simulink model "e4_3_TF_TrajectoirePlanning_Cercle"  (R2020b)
settings: Solver=FixedStepAuto  StartTime=0.0  StopTime=100  FixedStep=sampleTime  RelTol=1e-3  EnableMultiTasking=on
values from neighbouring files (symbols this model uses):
  k2_d_x = 1/1    (= 1)    [e4_3_TF_TrajectoirePlanning_code.m]    (also in e4_1_Model_TrajectoirePlanning_HITL_code.m = 0.5; e4_3_Model_TrajectoirePlanning_code.m = 0.5; e4_1_TF_TrajectoirePlanning_code.m; e4_1_Model_TrajectoirePlanning_code.m = 0.5)
  k2_d_y = 1/1    (= 1)    [e4_3_TF_TrajectoirePlanning_code.m]    (also in e4_1_Model_TrajectoirePlanning_HITL_code.m = 0.377358490566; e4_3_Model_TrajectoirePlanning_code.m = 0.377358490566; e4_1_TF_TrajectoirePlanning_code.m; e4_1_Model_TrajectoirePlanning_code.m = 0.377358490566)
  k2_d_z = 10    [e4_3_TF_TrajectoirePlanning_code.m]    (also in e4_1_Model_TrajectoirePlanning_HITL_code.m; e4_3_Model_TrajectoirePlanning_code.m; e4_1_TF_TrajectoirePlanning_code.m; e4_1_Model_TrajectoirePlanning_code.m)
  k2_p_x = 1/0.8    (= 1.25)    [e4_3_TF_TrajectoirePlanning_code.m]    (also in e4_1_Model_TrajectoirePlanning_HITL_code.m = 0.645161290323; e4_3_Model_TrajectoirePlanning_code.m = 0.645161290323; e4_1_TF_TrajectoirePlanning_code.m; e4_1_Model_TrajectoirePlanning_code.m = 0.645161290323)
  k2_p_y = 1/0.8    (= 1.25)    [e4_3_TF_TrajectoirePlanning_code.m]    (also in e4_1_Model_TrajectoirePlanning_HITL_code.m = 0.4; e4_3_Model_TrajectoirePlanning_code.m = 0.4; e4_1_TF_TrajectoirePlanning_code.m; e4_1_Model_TrajectoirePlanning_code.m = 0.4)
  k2_p_yaw = 1.6    [e4_3_TF_TrajectoirePlanning_code.m]    (also in e4_1_Model_TrajectoirePlanning_HITL_code.m; e4_3_Model_TrajectoirePlanning_code.m; e4_1_TF_TrajectoirePlanning_code.m; e4_1_Model_TrajectoirePlanning_code.m)
  k2_p_z = 1    [e4_3_TF_TrajectoirePlanning_code.m]    (also in e4_1_Model_TrajectoirePlanning_HITL_code.m; e4_3_Model_TrajectoirePlanning_code.m; e4_1_TF_TrajectoirePlanning_code.m; e4_1_Model_TrajectoirePlanning_code.m)
  sampleTime = 0.01    [startSimulation.m]    (also in start.m)
  saturation_psi = 2    [startSimulation.m]    (also in start.m)
  saturation_x = 2    [startSimulation.m]    (also in start.m)
  saturation_y = 2    [startSimulation.m]    (also in start.m)
  saturation_z = 2    [startSimulation.m]    (also in start.m)
libraries: simulink x2, aerolibanimutils x1

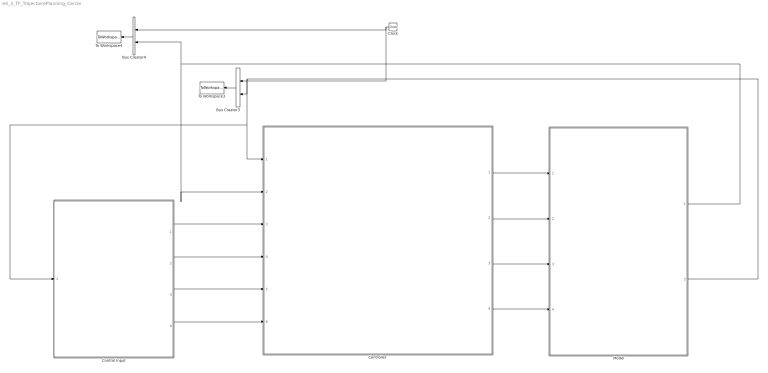
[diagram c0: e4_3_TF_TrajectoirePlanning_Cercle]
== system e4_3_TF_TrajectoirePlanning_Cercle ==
  Bus Creator3 : BusCreator  Inputs=2
  Bus Creator4 : BusCreator  Inputs=2
  Clock : Clock
  Control Input : Subsystem
  "Controller " : Subsystem
  Model : Subsystem
  To Workspace3 : ToWorkspace  VariableName=r1_pos_array  SampleTime=-1
  To Workspace4 : ToWorkspace  VariableName=r1_vel_array  SampleTime=-1
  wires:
  Clock/1 -> Bus Creator4/1, Bus Creator3/1
  Bus Creator3/1 -> To Workspace3/1
  Bus Creator4/1 -> To Workspace4/1
  Control Input/1(ux) -> "Controller "/3(Control input X)
  Control Input/2(uy) -> "Controller "/4(Control input Y)
  Control Input/3(uz) -> "Controller "/5(Control input H)
  Control Input/4(upsi) -> "Controller "/6(Control input Psi)
  Model/2(Output Position) -> "Controller "/1(Feedback Position), Control Input/1(Position Feedback), Bus Creator3/2
  Model/1(Output Velocity) -> "Controller "/2(Feedback Velocity), Bus Creator4/2
  "Controller "/1(Controller Output X) -> Model/1(Commande Input X)
  "Controller "/4(Controller Output Psi) -> Model/4(Commande Input Psi)
  "Controller "/2(Controller Output Y) -> Model/2(Commande Input Y)
  "Controller "/3(Controller Output H) -> Model/3(Commande Input H)

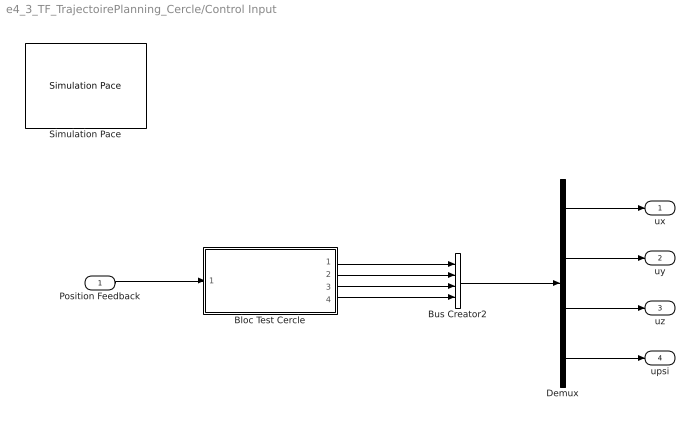
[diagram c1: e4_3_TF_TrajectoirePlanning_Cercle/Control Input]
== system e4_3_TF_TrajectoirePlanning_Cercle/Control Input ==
  Position Feedback : Inport
  Bloc Test Cercle : Subsystem
  Bus Creator2 : BusCreator  Inputs=4
  Demux : Demux
  Simulation Pace : aerolibanimutils/Simulation Pace  SimulationPace=100  SleepMode=MATLAB Thread  OutputPaceError=off  SampleTime=-1
  ux : Outport  VectorParamsAs1DForOutWhenUnconnected=off
  uy : Outport  Port=2  VectorParamsAs1DForOutWhenUnconnected=off
  uz : Outport  Port=3  VectorParamsAs1DForOutWhenUnconnected=off
  upsi : Outport  Port=4  VectorParamsAs1DForOutWhenUnconnected=off
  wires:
  Demux/2 -> uy/1
  Demux/1 -> ux/1
  Demux/3 -> uz/1
  Demux/4 -> upsi/1
  Bloc Test Cercle/2(uy) -> Bus Creator2/2
  Bloc Test Cercle/4(upsi) -> Bus Creator2/4
  Position Feedback/1 -> Bloc Test Cercle/1(Position Feedback)
  Bloc Test Cercle/3(uz) -> Bus Creator2/3
  Bus Creator2/1 -> Demux/1
  Bloc Test Cercle/1(ux) -> Bus Creator2/1

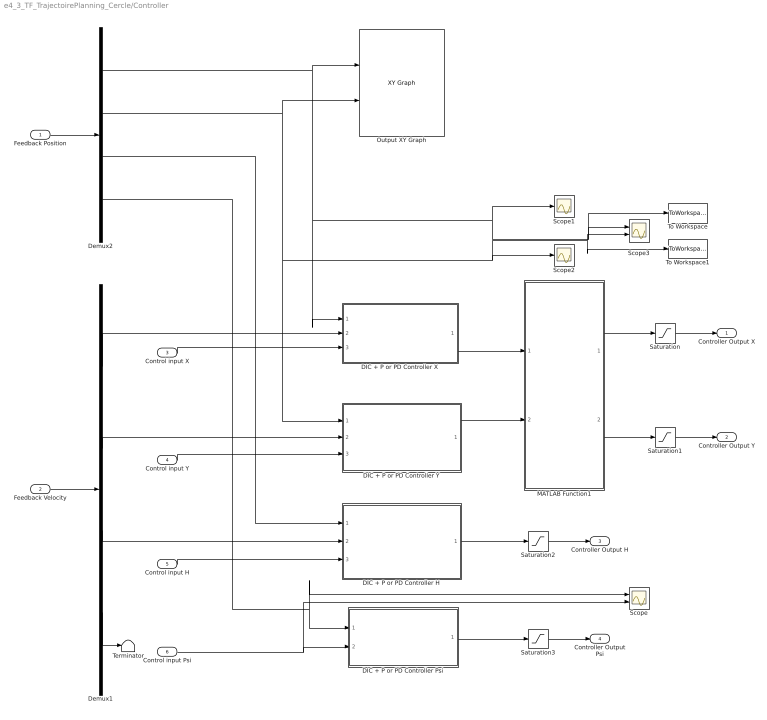
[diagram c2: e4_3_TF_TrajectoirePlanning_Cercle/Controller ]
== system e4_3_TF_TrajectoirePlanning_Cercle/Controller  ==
  Feedback Position : Inport
  Feedback Velocity : Inport  Port=2
  Control input X : Inport  Port=3
  Control input Y : Inport  Port=4
  Control input H : Inport  Port=5
  Control input Psi : Inport  Port=6
  DIC + P or PD Controller H : Subsystem
  DIC + P or PD Controller Psi : Subsystem
  DIC + P or PD Controller X : Subsystem
  DIC + P or PD Controller Y : Subsystem
  Demux1 : Demux
  Demux2 : Demux
  MATLAB Function1 : MATLAB Function  TreatAsAtomicUnit=on
  Output XY Graph : simulink/Sinks/XY Graph  xmin=-3  xmax=3  ymin=-3  ymax=3  st=-1
  Saturation : Saturate  UpperLimit=saturation_x  LowerLimit=-saturation_x
  Saturation1 : Saturate  UpperLimit=saturation_y  LowerLimit=-saturation_y
  Saturation2 : Saturate  UpperLimit=saturation_z  LowerLimit=-saturation_z
  Saturation3 : Saturate  UpperLimit=saturation_psi  LowerLimit=-saturation_psi
  Scope : Scope  NumInputPorts=2
  Scope1 : Scope
  Scope2 : Scope
  Scope3 : Scope  NumInputPorts=2
  Terminator : Terminator
  To Workspace : ToWorkspace  VariableName=x_desire  SampleTime=-1
  To Workspace1 : ToWorkspace  VariableName=y_desire  SampleTime=-1
  Controller Output X : Outport  VectorParamsAs1DForOutWhenUnconnected=off
  Controller Output Y : Outport  Port=2  VectorParamsAs1DForOutWhenUnconnected=off
  Controller Output H : Outport  Port=3  VectorParamsAs1DForOutWhenUnconnected=off
  Controller Output Psi : Outport  Port=4  VectorParamsAs1DForOutWhenUnconnected=off
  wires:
  Feedback Position/1 -> Demux2/1
  Feedback Velocity/1 -> Demux1/1
  Demux1/2 -> DIC + P or PD Controller Y/2(Feedback Velocity Y)
  Demux2/3 -> DIC + P or PD Controller H/1(Feedback Position H)
  Demux1/1 -> DIC + P or PD Controller X/2(Feedback Velocity X)
  Demux1/3 -> DIC + P or PD Controller H/2(Feedback Velocity H)
  Control input X/1 -> DIC + P or PD Controller X/3(Control Input X)
  Control input Psi/1 -> Scope/2, DIC + P or PD Controller Psi/2(Control input Psi)
  Control input H/1 -> DIC + P or PD Controller H/3(Control Input H)
  Saturation/1 -> Controller Output X/1
  Saturation1/1 -> Controller Output Y/1
  Saturation2/1 -> Controller Output H/1
  Saturation3/1 -> Controller Output Psi/1
  Control input Y/1 -> DIC + P or PD Controller Y/3(Control Input Y)
  DIC + P or PD Controller H/1(Controller Output H) -> Saturation2/1
  DIC + P or PD Controller Psi/1(Controller Output Psi) -> Saturation3/1
  Demux2/4 -> Scope/1, DIC + P or PD Controller Psi/1(Feedback Position Psi)
  Demux1/4 -> Terminator/1
  DIC + P or PD Controller Y/1(Controller Output Y) -> MATLAB Function1/2(eay)
  MATLAB Function1/2(phi) -> Saturation1/1
  MATLAB Function1/1(theta) -> Saturation/1
  DIC + P or PD Controller X/1(Controller Output X) -> MATLAB Function1/1(eax)
  Demux2/1 -> DIC + P or PD Controller X/1(Feedback Position X), Scope3/1, To Workspace/1, Scope1/1, Output XY Graph/1
  Demux2/2 -> DIC + P or PD Controller Y/1(Feedback Position Y), Scope3/2, To Workspace1/1, Scope2/1, Output XY Graph/2

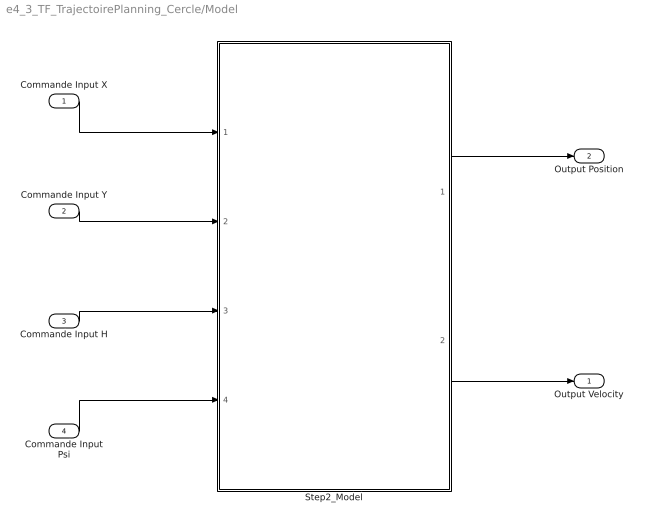
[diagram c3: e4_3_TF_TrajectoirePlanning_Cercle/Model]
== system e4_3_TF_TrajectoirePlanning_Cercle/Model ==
  Commande Input X : Inport
  Commande Input Y : Inport  Port=2
  Commande Input H : Inport  Port=3
  Commande Input Psi : Inport  Port=4
  Step2_Model : Subsystem
  Output Velocity : Outport  VectorParamsAs1DForOutWhenUnconnected=off
  Output Position : Outport  Port=2  VectorParamsAs1DForOutWhenUnconnected=off
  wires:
  Commande Input Y/1 -> Step2_Model/2(In2)
  Commande Input Psi/1 -> Step2_Model/4(In4)
  Commande Input H/1 -> Step2_Model/3(In3)
  Step2_Model/1(Position) -> Output Position/1
  Commande Input X/1 -> Step2_Model/1(In1)
  Step2_Model/2(Velocity) -> Output Velocity/1

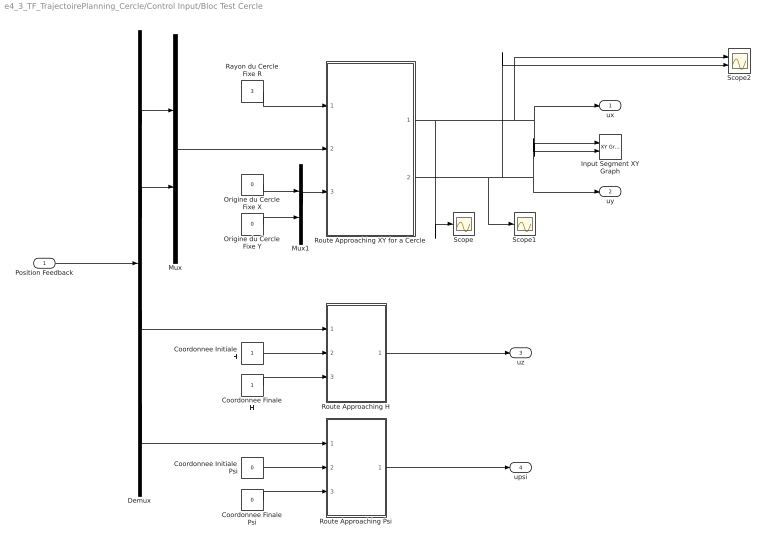
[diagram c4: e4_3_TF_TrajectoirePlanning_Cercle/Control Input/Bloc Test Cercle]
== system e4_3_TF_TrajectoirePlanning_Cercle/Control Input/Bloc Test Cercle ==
  Position Feedback : Inport
  Coordonnee Finale H : Constant
  Coordonnee Finale Psi : Constant  Value=0
  Coordonnee Initiale H : Constant
  Coordonnee Initiale Psi : Constant  Value=0
  Demux : Demux
  Input Segment XY Graph : simulink/Sinks/XY Graph  xmin=-10  xmax=10  ymin=-10  ymax=10  st=-1
  Mux : Mux  Inputs=2
  Mux1 : Mux  Inputs=2
  Origine du Cercle Fixe X : Constant  Value=0
  Origine du Cercle Fixe Y : Constant  Value=0
  Rayon du Cercle Fixe R : Constant  Value=3
  Route Approaching H : MATLAB Function  TreatAsAtomicUnit=on  SystemSampleTime=sampleTime
  Route Approaching Psi : MATLAB Function  TreatAsAtomicUnit=on  SystemSampleTime=sampleTime
  Route Approaching XY for a Cercle : MATLAB Function  TreatAsAtomicUnit=on  SystemSampleTime=sampleTime
  Scope : Scope
  Scope1 : Scope
  Scope2 : Scope  NumInputPorts=2
  ux : Outport  VectorParamsAs1DForOutWhenUnconnected=off
  uy : Outport  Port=2  VectorParamsAs1DForOutWhenUnconnected=off
  uz : Outport  Port=3  VectorParamsAs1DForOutWhenUnconnected=off
  upsi : Outport  Port=4  VectorParamsAs1DForOutWhenUnconnected=off
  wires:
  Position Feedback/1 -> Demux/1
  Coordonnee Finale H/1 -> Route Approaching H/3(P_final)
  Coordonnee Finale Psi/1 -> Route Approaching Psi/3(P_final)
  Coordonnee Initiale Psi/1 -> Route Approaching Psi/2(P_init)
  Route Approaching H/1(P_d) -> uz/1
  Route Approaching Psi/1(P_d) -> upsi/1
  Demux/3 -> Route Approaching H/1(P_feedback)
  Demux/2 -> Mux/2
  Demux/4 -> Route Approaching Psi/1(P_feedback)
  Coordonnee Initiale H/1 -> Route Approaching H/2(P_init)
  Demux/1 -> Mux/1
  Mux/1 -> Route Approaching XY for a Cercle/2(P_feedback)
  Rayon du Cercle Fixe R/1 -> Route Approaching XY for a Cercle/1(P_Rayon)
  Mux1/1 -> Route Approaching XY for a Cercle/3(P_Origine)
  Origine du Cercle Fixe X/1 -> Mux1/1
  Origine du Cercle Fixe Y/1 -> Mux1/2
  Route Approaching XY for a Cercle/2(P_dy) -> Scope2/2, uy/1, Input Segment XY Graph/2, Scope1/1
  Route Approaching XY for a Cercle/1(P_dx) -> Scope2/1, ux/1, Input Segment XY Graph/1, Scope/1

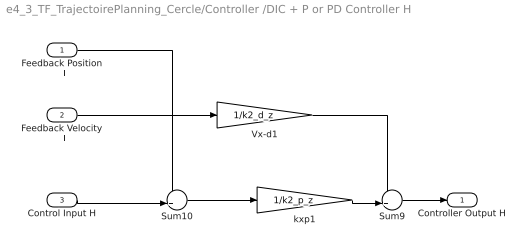
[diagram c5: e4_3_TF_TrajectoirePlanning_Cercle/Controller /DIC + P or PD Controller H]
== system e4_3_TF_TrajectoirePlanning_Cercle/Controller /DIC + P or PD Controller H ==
  Feedback Position H : Inport
  Feedback Velocity H : Inport  Port=2
  Control Input H : Inport  Port=3
  Sum10 : Sum  Inputs=-+|
  Sum9 : Sum  Inputs=-+|
  Vx-d1 : Gain  Gain=1/k2_d_z
  kxp1 : Gain  Gain=1/k2_p_z
  Controller Output H : Outport  VectorParamsAs1DForOutWhenUnconnected=off
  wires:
  Sum9/1 -> Controller Output H/1
  Feedback Velocity H/1 -> Vx-d1/1
  Sum10/1 -> kxp1/1
  kxp1/1 -> Sum9/2
  Vx-d1/1 -> Sum9/1
  Control Input H/1 -> Sum10/2
  Feedback Position H/1 -> Sum10/1

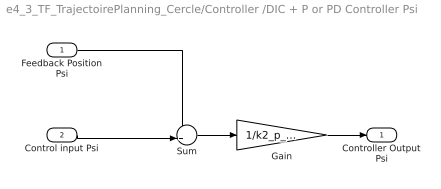
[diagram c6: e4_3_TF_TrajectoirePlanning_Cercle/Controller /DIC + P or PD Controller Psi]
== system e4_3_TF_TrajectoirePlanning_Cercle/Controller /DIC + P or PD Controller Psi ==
  Feedback Position Psi : Inport
  Control input Psi : Inport  Port=2
  Gain : Gain  Gain=1/k2_p_yaw
  Sum : Sum  Inputs=-+|
  Controller Output Psi : Outport  VectorParamsAs1DForOutWhenUnconnected=off
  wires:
  Gain/1 -> Controller Output Psi/1
  Sum/1 -> Gain/1
  Control input Psi/1 -> Sum/2
  Feedback Position Psi/1 -> Sum/1

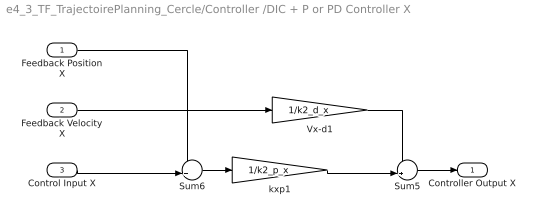
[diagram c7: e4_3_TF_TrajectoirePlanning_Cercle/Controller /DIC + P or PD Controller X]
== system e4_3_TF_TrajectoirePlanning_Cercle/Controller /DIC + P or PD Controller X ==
  Feedback Position X : Inport
  Feedback Velocity X : Inport  Port=2
  Control Input X : Inport  Port=3
  Sum5 : Sum  Inputs=-+|
  Sum6 : Sum  Inputs=-+|
  Vx-d1 : Gain  Gain=1/k2_d_x
  kxp1 : Gain  Gain=1/k2_p_x
  Controller Output X : Outport  VectorParamsAs1DForOutWhenUnconnected=off
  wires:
  Vx-d1/1 -> Sum5/1
  kxp1/1 -> Sum5/2
  Sum5/1 -> Controller Output X/1
  Sum6/1 -> kxp1/1
  Control Input X/1 -> Sum6/2
  Feedback Velocity X/1 -> Vx-d1/1
  Feedback Position X/1 -> Sum6/1

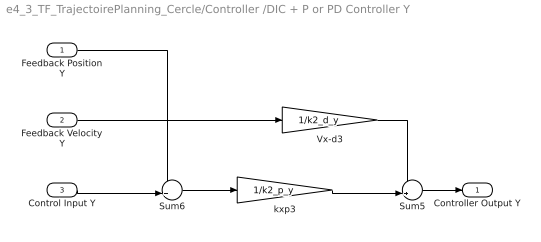
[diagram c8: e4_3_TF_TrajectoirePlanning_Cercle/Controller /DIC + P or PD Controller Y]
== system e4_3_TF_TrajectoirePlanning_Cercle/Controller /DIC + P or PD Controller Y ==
  Feedback Position Y : Inport
  Feedback Velocity Y : Inport  Port=2
  Control Input Y : Inport  Port=3
  Sum5 : Sum  Inputs=-+|
  Sum6 : Sum  Inputs=-+|
  Vx-d3 : Gain  Gain=1/k2_d_y
  kxp3 : Gain  Gain=1/k2_p_y
  Controller Output Y : Outport  VectorParamsAs1DForOutWhenUnconnected=off
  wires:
  Feedback Velocity Y/1 -> Vx-d3/1
  Feedback Position Y/1 -> Sum6/1
  Sum6/1 -> kxp3/1
  kxp3/1 -> Sum5/2
  Vx-d3/1 -> Sum5/1
  Sum5/1 -> Controller Output Y/1
  Control Input Y/1 -> Sum6/2

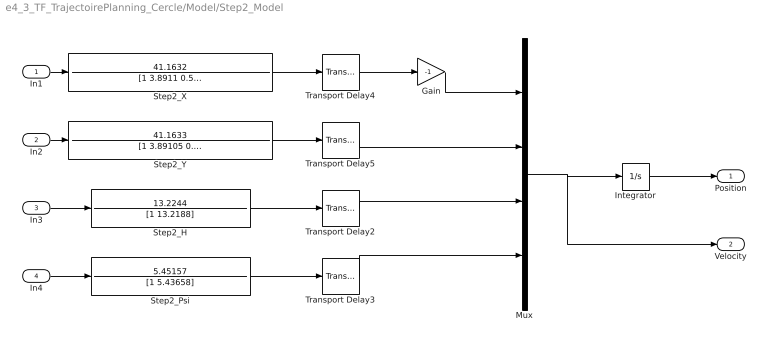
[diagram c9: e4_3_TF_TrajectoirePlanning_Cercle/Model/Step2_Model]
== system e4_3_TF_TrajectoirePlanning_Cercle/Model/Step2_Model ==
  In1 : Inport
  In2 : Inport  Port=2
  In3 : Inport  Port=3
  In4 : Inport  Port=4
  Gain : Gain  Gain=-1
  Integrator : Integrator
  Mux : Mux
  Step2_H : TransferFcn  Numerator=13.2244  Denominator=[1 13.2188]
  Step2_Psi : TransferFcn  Numerator=5.45157  Denominator=[1 5.43658]
  Step2_X : TransferFcn  Numerator=41.1632  Denominator=[1 3.8911 0.529635]
  Step2_Y : TransferFcn  Numerator=41.1633  Denominator=[1 3.89105 0.529839]
  Transport Delay2 : TransportDelay  DelayTime=0.0344
  Transport Delay3 : TransportDelay  DelayTime=0.0313
  Transport Delay4 : TransportDelay  DelayTime=0.0289
  Transport Delay5 : TransportDelay  DelayTime=0.0289
  Position : Outport  VectorParamsAs1DForOutWhenUnconnected=off
  Velocity : Outport  Port=2  VectorParamsAs1DForOutWhenUnconnected=off
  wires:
  Transport Delay2/1 -> Mux/3
  In2/1 -> Step2_Y/1
  In4/1 -> Step2_Psi/1
  Transport Delay3/1 -> Mux/4
  In1/1 -> Step2_X/1
  In3/1 -> Step2_H/1
  Step2_H/1 -> Transport Delay2/1
  Step2_Y/1 -> Transport Delay5/1
  Step2_X/1 -> Transport Delay4/1
  Step2_Psi/1 -> Transport Delay3/1
  Transport Delay4/1 -> Gain/1
  Transport Delay5/1 -> Mux/2
  Integrator/1 -> Position/1
  Mux/1 -> Velocity/1, Integrator/1
  Gain/1 -> Mux/1

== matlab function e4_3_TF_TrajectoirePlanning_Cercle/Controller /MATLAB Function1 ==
function [theta,phi] = fcn(eax,eay)
g=9.8;

theta =-eax/g;% vx
phi =eay/g;% vy

== matlab function e4_3_TF_TrajectoirePlanning_Cercle/Control Input/Bloc Test 
Cercle/Route Approaching H ==
function P_d = fcn(P_feedback, P_init, P_final)

% determine the constants
a0  = 10;

% the parameters of PD controller: 1/k2
% according to P287 of 《多旋翼飞行器设计与控制》,
% these two parameters should be equal? Is that true?

% global k2_p_z;
% global k2_d_z;
% k2_p_z=0.1;
% k2_d_z=0.1;

% the parameter of 'approaching'
k0_z=0.1;
k1_z=1;

persistent P_static;
if isempty(P_static)
    P_static=0; % the initilized value of position for giving a initial UAV position
end

P_static = P_feedback;

% the iterative process
P_perp = P_final+(P_init-P_final)*((P_static-P_final)'*(P_init-P_final))/(norm(P_final-P_init + 0.000001))^2;
% this extra '+ 0.000001' is for avoiding that 
% the zero denominator turns to zero.
temp  = satgd(k0_z*(P_final - P_static)+k1_z*(P_perp-P_static),a0);
P_d = P_static + temp;

== matlab function e4_3_TF_TrajectoirePlanning_Cercle/Control Input/Bloc Test 
Cercle/Route Approaching Psi ==
function P_d = fcn(P_feedback, P_init, P_final)

% determine the constants
a0  = 10;

% the parameters of PD controller: 1/k2
% according to P287 of 《多旋翼飞行器设计与控制》,
% these two parameters should be equal? Is that true?

% global k2_p_yaw;
% global k2_d_yaw;
% k2_p_yaw=0.1;
% k2_d_yaw=0.1;

% the parameter of 'approaching'
k0_yaw=0.1;
k1_yaw=1;

persistent P_static;
if isempty(P_static)
    P_static=0; % the initilized value of position for giving a initial UAV position
end

P_static = P_feedback;

% the iterative process
P_perp = P_final+(P_init-P_final)*((P_static-P_final)'*(P_init-P_final))/(norm(P_final-P_init + 0.000001))^2;
% this extra '+ 0.000001' is for avoiding that 
% the zero denominator turns to zero.
temp  = satgd(k0_yaw*(P_final - P_static)+k1_yaw*(P_perp-P_static),a0);
P_d = P_static + temp;

== matlab function e4_3_TF_TrajectoirePlanning_Cercle/Control Input/Bloc Test 
Cercle/Route Approaching XY for a Cercle ==
function [P_dx,P_dy] = fcn(P_Rayon, P_feedback, P_Origine)

% determine the constants
a0  = 3;
% the parameters of PD controller: 1/k2
% according to P287 of 《多旋翼飞行器设计与控制》,
% these two parameters should be equal? Is that true?
% global k2_p_x;
% global k2_d_x;
% k2_p_x=0.1;
% k2_d_x=0.1;
% the parameter of 'approaching'
% k0_x=0.3;
% k1_x=0.3;
% k0_x=0.3;
% k1_x=0.7;
k0_x=0.3;
k1_x=1;

% Determine the navagation points for a cercle, four for the condition
% Point_1=[P_Origine(1)-P_Rayon;P_Origine(2)];
% Point_2=[P_Origine(1);P_Origine(2)+P_Rayon];
% Point_3=[P_Origine(1)+P_Rayon;P_Origine(2)];
% Point_4=[P_Origine(1);P_Origine(2)-P_Rayon];
% Point=[Point_1,Point_2,Point_3,Point_4];
% P_init=[0;0]; % the initialized position of UAV
% Distance=sqrt((Point(1,:)-P_init(1)).^2+(Point(2,:)-P_init(2)).^2);
% JL_data = [Point;Distance];
% [d,indice]=sort(JL_data(3,:));
% Point_start=Point(:,indice(1));

P_init=[0;0]; % the initialized position of UAV
persistent P_static;
if isempty(P_static)
    P_static=P_init; % the initilized value of position for giving a initial UAV position
end
P_static = P_feedback; % Except the initialization, the following position is gotten by the feedback 

% the iterative process
P_perp_rayon = P_Origine+(P_static-P_Origine)*(P_Rayon/(norm((P_static-P_Origine)+ 0.000001)));
A = P_Rayon*[0,1;-1,0]*(((P_perp_rayon - P_Origine)+0.000001)/(norm((P_perp_rayon - P_Origine))+0.000001));
temp  = satgd(k0_x*A+k1_x*(P_perp_rayon-P_static),a0);
P_d0 = P_static + temp;
P_dx=P_d0(1);
P_dy=P_d0(2);
